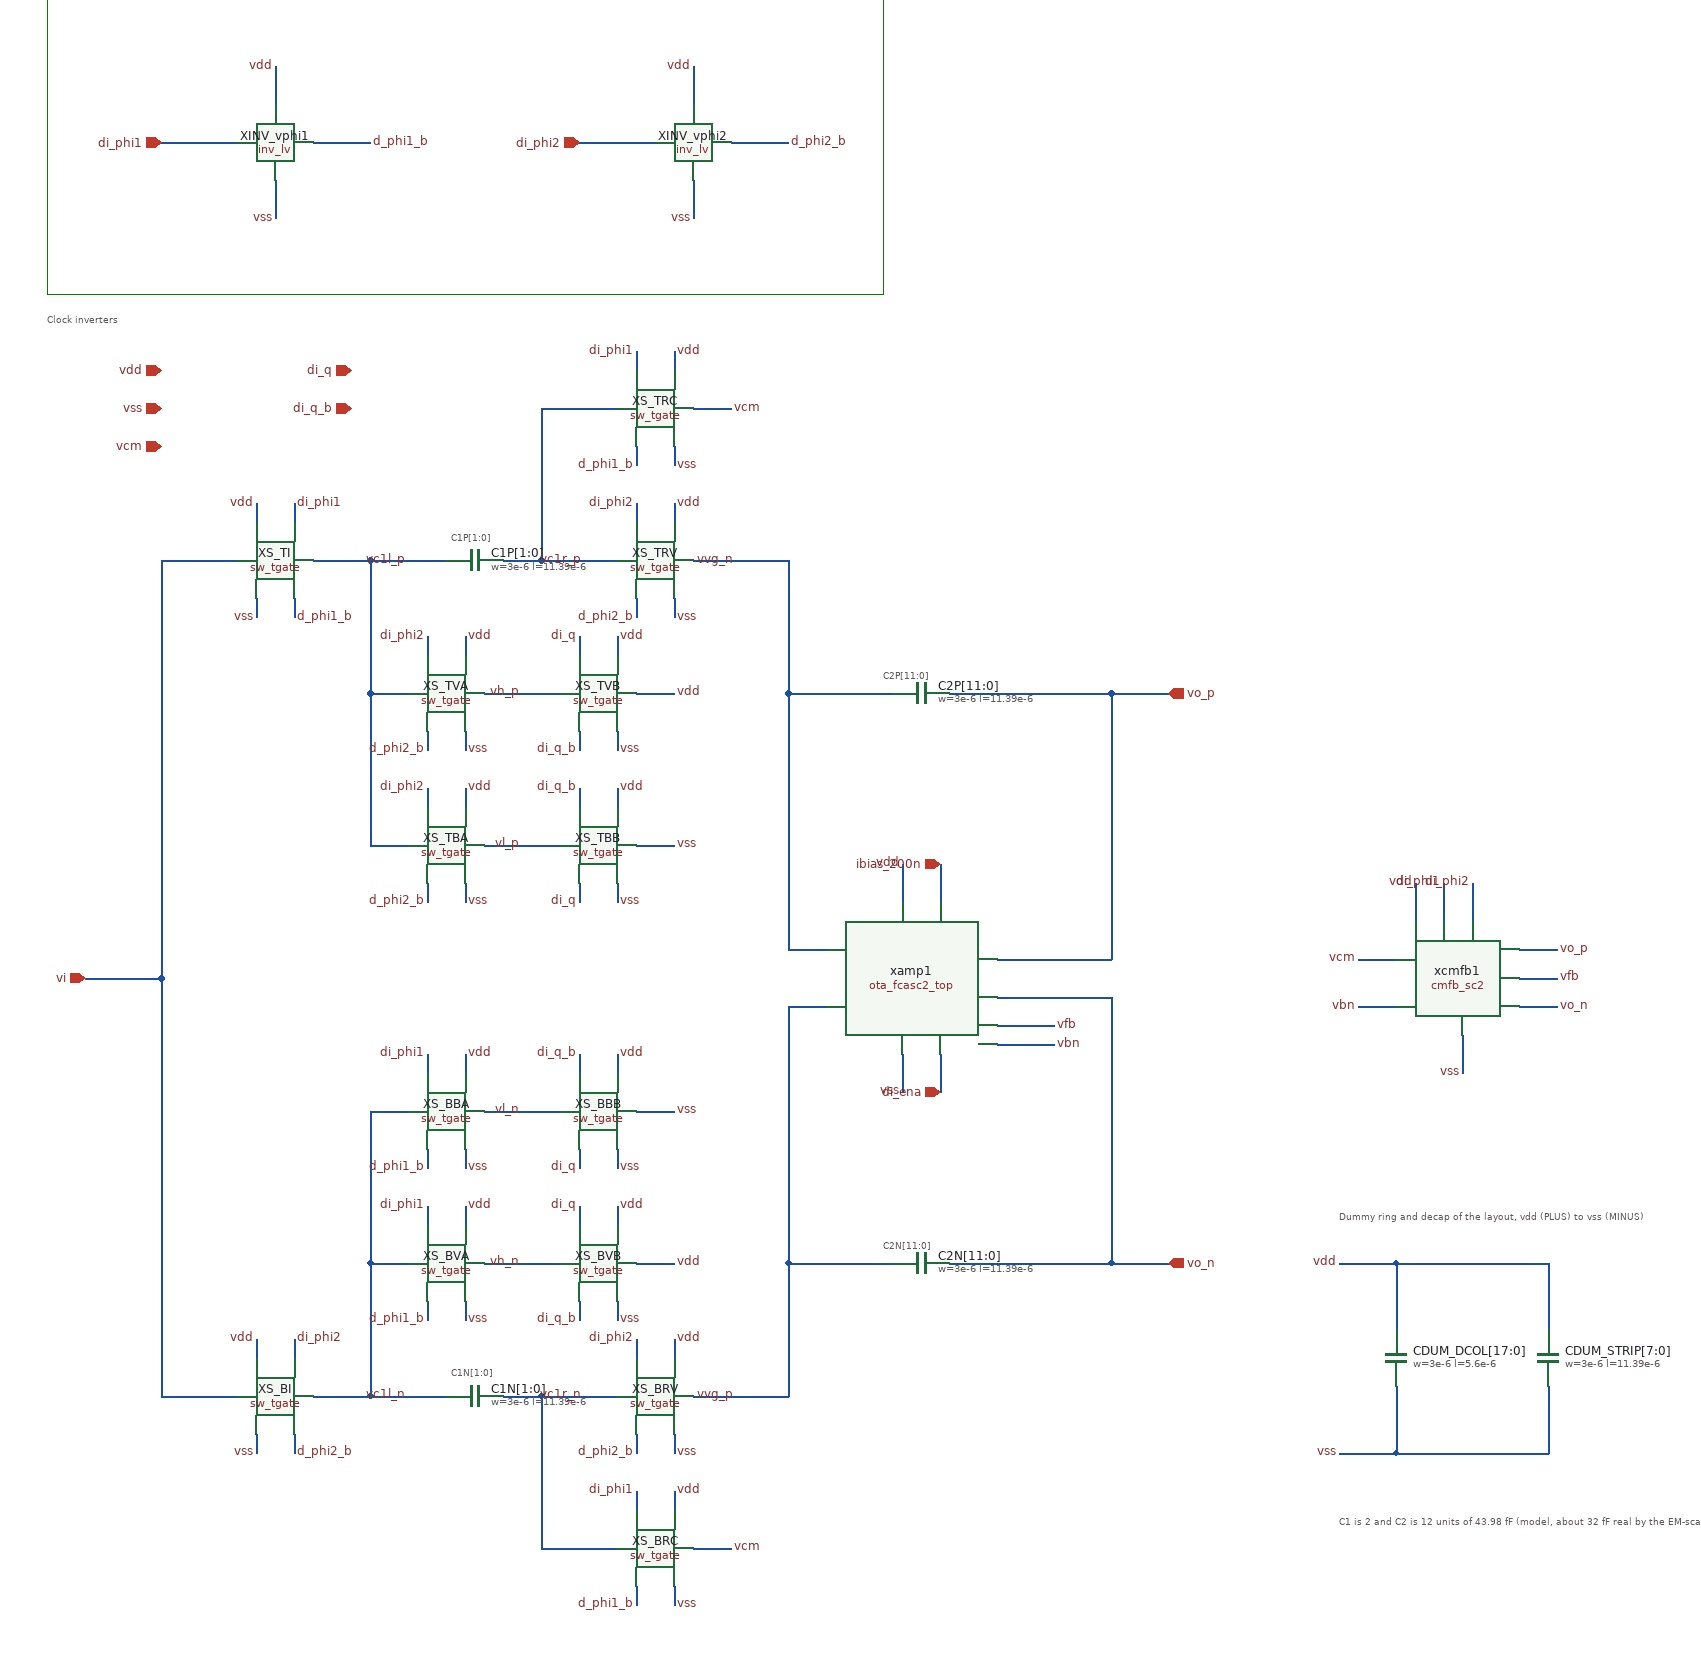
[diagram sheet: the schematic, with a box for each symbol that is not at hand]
v {xschem version=3.4.8RC file_version=1.3}
G {}
K {}
V {}
S {}
F {}
E {}
P 4 5 20 -1040 900 -1040 900 -720 20 -720 20 -1040 {dash = 8}
T {C1P[1:0]} 445 -476 0 0 0.2 0.2 {}
T {C2P[11:0]} 900 -330 0 0 0.2 0.2 {}
T {C1N[1:0]} 445 404 0 0 0.2 0.2 {}
T {C2N[11:0]} 900 270 0 0 0.2 0.2 {}
T {Clock inverters} 20 -705 0 0 0.25 0.25 {}
T {C1 is 2 and C2 is 12 units of 43.98 fF (model, about 32 fF real by the EM-scaled estimate) per half, C1/C2 = 1/6 by unit count, a1 = 2 C1/C2 = 1/3} 1380 560 0 0 0.25 0.25 {}
T {Dummy ring and decap of the layout, vdd (PLUS) to vss (MINUS)} 1380 240 0 0 0.3 0.3 {}
N 280 -500 280 -480 {lab=di_phi1}
N 280 -400 280 -380 {lab=d_phi1_b}
N 240 -500 240 -480 {lab=vdd}
N 240 -400 240 -380 {lab=vss}
N 140 -440 220 -440 {lab=vi}
N 360 -440 440 -440 {lab=vc1l_p}
N 360 -300 360 -140 {lab=vc1l_p}
N 360 -300 400 -300 {lab=vc1l_p}
N 360 -140 400 -140 {lab=vc1l_p}
N 420 -360 420 -340 {lab=di_phi2}
N 420 -260 420 -240 {lab=d_phi2_b}
N 460 -360 460 -340 {lab=vdd}
N 460 -260 460 -240 {lab=vss}
N 580 -360 580 -340 {lab=di_q}
N 580 -260 580 -240 {lab=di_q_b}
N 620 -360 620 -340 {lab=vdd}
N 620 -260 620 -240 {lab=vss}
N 480 -300 560 -300 {lab=vh_p}
N 640 -300 680 -300 {lab=vdd}
N 420 -200 420 -180 {lab=di_phi2}
N 420 -100 420 -80 {lab=d_phi2_b}
N 460 -200 460 -180 {lab=vdd}
N 460 -100 460 -80 {lab=vss}
N 580 -200 580 -180 {lab=di_q_b}
N 580 -100 580 -80 {lab=di_q}
N 620 -200 620 -180 {lab=vdd}
N 620 -100 620 -80 {lab=vss}
N 480 -140 560 -140 {lab=vl_p}
N 640 -140 680 -140 {lab=vss}
N 540 -440 620 -440 {lab=vc1r_p}
N 540 -600 540 -440 {lab=vc1r_p}
N 540 -600 620 -600 {lab=vc1r_p}
N 640 -660 640 -640 {lab=di_phi1}
N 640 -560 640 -540 {lab=d_phi1_b}
N 680 -660 680 -640 {lab=vdd}
N 680 -560 680 -540 {lab=vss}
N 640 -500 640 -480 {lab=di_phi2}
N 640 -400 640 -380 {lab=d_phi2_b}
N 680 -500 680 -480 {lab=vdd}
N 680 -400 680 -380 {lab=vss}
N 700 -600 740 -600 {lab=vcm}
N 700 -440 800 -440 {lab=vvg_n}
N 800 -300 800 -30 {lab=vvg_n}
N 800 -30 840 -30 {lab=vvg_n}
N 800 -300 910 -300 {lab=vvg_n}
N 970 -300 1140 -300 {lab=vo_p}
N 1140 -300 1200 -300 {lab=vo_p}
N 1140 -300 1140 -20 {lab=vo_p}
N 1020 -20 1140 -20 {lab=vo_p}
N 280 380 280 400 {lab=di_phi2}
N 280 480 280 500 {lab=d_phi2_b}
N 240 380 240 400 {lab=vdd}
N 240 480 240 500 {lab=vss}
N 140 440 220 440 {lab=vi}
N 360 440 440 440 {lab=vc1l_n}
N 360 300 360 440 {lab=vc1l_n}
N 360 300 400 300 {lab=vc1l_n}
N 360 140 400 140 {lab=vc1l_n}
N 420 240 420 260 {lab=di_phi1}
N 420 340 420 360 {lab=d_phi1_b}
N 460 240 460 260 {lab=vdd}
N 460 340 460 360 {lab=vss}
N 580 240 580 260 {lab=di_q}
N 580 340 580 360 {lab=di_q_b}
N 620 240 620 260 {lab=vdd}
N 620 340 620 360 {lab=vss}
N 480 300 560 300 {lab=vh_n}
N 640 300 680 300 {lab=vdd}
N 420 80 420 100 {lab=di_phi1}
N 420 180 420 200 {lab=d_phi1_b}
N 460 80 460 100 {lab=vdd}
N 460 180 460 200 {lab=vss}
N 580 80 580 100 {lab=di_q_b}
N 580 180 580 200 {lab=di_q}
N 620 80 620 100 {lab=vdd}
N 620 180 620 200 {lab=vss}
N 480 140 560 140 {lab=vl_n}
N 640 140 680 140 {lab=vss}
N 540 440 620 440 {lab=vc1r_n}
N 540 440 540 600 {lab=vc1r_n}
N 540 600 620 600 {lab=vc1r_n}
N 640 540 640 560 {lab=di_phi1}
N 640 640 640 660 {lab=d_phi1_b}
N 680 540 680 560 {lab=vdd}
N 680 640 680 660 {lab=vss}
N 640 380 640 400 {lab=di_phi2}
N 640 480 640 500 {lab=d_phi2_b}
N 680 380 680 400 {lab=vdd}
N 680 480 680 500 {lab=vss}
N 700 600 740 600 {lab=vcm}
N 700 440 800 440 {lab=vvg_p}
N 800 300 800 440 {lab=vvg_p}
N 800 30 840 30 {lab=vvg_p}
N 800 300 910 300 {lab=vvg_p}
N 970 300 1140 300 {lab=vo_n}
N 1140 300 1200 300 {lab=vo_n}
N 1140 20 1140 300 {lab=vo_n}
N 1020 20 1140 20 {lab=vo_n}
N 60 0 140 0 {lab=vi}
N 140 0 140 440 {lab=vi}
N 920 -120 920 -80 {lab=vdd}
N 960 -120 960 -80 {lab=ibias_200n}
N 920 80 920 120 {lab=vss}
N 960 80 960 120 {lab=di_ena}
N 1020 50 1080 50 {lab=vfb}
N 1020 70 1080 70 {lab=vbn}
N 1490 -100 1490 -60 {lab=di_phi1}
N 1520 -100 1520 -60 {lab=di_phi2}
N 1460 -100 1460 -60 {lab=vdd}
N 1510 60 1510 100 {lab=vss}
N 1400 -20 1440 -20 {lab=vcm}
N 1400 30 1440 30 {lab=vbn}
N 1570 -30 1610 -30 {lab=vo_p}
N 1570 0 1610 0 {lab=vfb}
N 1570 30 1610 30 {lab=vo_n}
N 140 -880 220 -880 {lab=di_phi1}
N 300 -880 360 -880 {lab=d_phi1_b}
N 260 -960 260 -920 {lab=vdd}
N 260 -840 260 -800 {lab=vss}
N 580 -880 660 -880 {lab=di_phi2}
N 740 -880 800 -880 {lab=d_phi2_b}
N 700 -960 700 -920 {lab=vdd}
N 700 -840 700 -800 {lab=vss}
N 1440 300 1440 370 {lab=vdd}
N 1440 430 1440 500 {lab=vss}
N 1600 300 1600 370 {lab=vdd}
N 1600 430 1600 500 {lab=vss}
N 300 -440 360 -440 {lab=vc1l_p}
N 360 -440 360 -300 {lab=vc1l_p}
N 500 -440 540 -440 {lab=vc1r_p}
N 800 -440 800 -300 {lab=vvg_n}
N 300 440 360 440 {lab=vc1l_n}
N 360 140 360 300 {lab=vc1l_n}
N 500 440 540 440 {lab=vc1r_n}
N 800 30 800 300 {lab=vvg_p}
N 140 -440 140 0 {lab=vi}
N 1380 300 1440 300 {lab=vdd}
N 1380 500 1440 500 {lab=vss}
N 1440 300 1600 300 {lab=vdd}
N 1440 500 1600 500 {lab=vss}
C {sw_tgate.sym} 260 -440 0 1 {name=XS_TI
}
C {sw_tgate.sym} 440 -300 0 0 {name=XS_TVA
}
C {sw_tgate.sym} 600 -300 0 0 {name=XS_TVB
}
C {sw_tgate.sym} 440 -140 0 0 {name=XS_TBA
}
C {sw_tgate.sym} 600 -140 0 0 {name=XS_TBB
}
C {cap_cmomf.sym} 470 -440 1 0 {name=C1P[1:0]
model=cap_cmomf
w=3e-6
l=11.39e-6
mmin=1
mmax=4
subblock=0
m=1
mm_ok=1
spiceprefix=X
hide_texts=true
}
C {sw_tgate.sym} 660 -440 0 0 {name=XS_TRV
}
C {sw_tgate.sym} 660 -600 0 0 {name=XS_TRC
}
C {sw_tgate.sym} 260 440 0 1 {name=XS_BI
}
C {sw_tgate.sym} 440 300 0 0 {name=XS_BVA
}
C {sw_tgate.sym} 600 300 0 0 {name=XS_BVB
}
C {sw_tgate.sym} 440 140 0 0 {name=XS_BBA
}
C {sw_tgate.sym} 600 140 0 0 {name=XS_BBB
}
C {cap_cmomf.sym} 470 440 1 0 {name=C1N[1:0]
model=cap_cmomf
w=3e-6
l=11.39e-6
mmin=1
mmax=4
subblock=0
m=1
mm_ok=1
spiceprefix=X
hide_texts=true
}
C {sw_tgate.sym} 660 440 0 0 {name=XS_BRV
}
C {sw_tgate.sym} 660 600 0 0 {name=XS_BRC
}
C {ipin.sym} 60 0 0 0 {name=p3 lab=vi}
C {ota_fcasc2_top.sym} 840 -30 0 0 {name=xamp1
}
C {ipin.sym} 960 -120 1 0 {name=p9 lab=ibias_200n}
C {ipin.sym} 960 120 3 0 {name=p10 lab=di_ena}
C {cap_cmomf.sym} 940 -300 3 0 {name=C2P[11:0]
model=cap_cmomf
w=3e-6
l=11.39e-6
mmin=1
mmax=4
subblock=0
m=1
mm_ok=1
spiceprefix=X
hide_texts=true
}
C {cap_cmomf.sym} 940 300 3 0 {name=C2N[11:0]
model=cap_cmomf
w=3e-6
l=11.39e-6
mmin=1
mmax=4
subblock=0
m=1
mm_ok=1
spiceprefix=X
hide_texts=true
}
C {cmfb_sc2.sym} 1440 -60 0 0 {name=xcmfb1
}
C {inv_lv.sym} 260 -880 0 0 {name=XINV_vphi1
}
C {ipin.sym} 140 -880 0 0 {name=p5 lab=di_phi1}
C {inv_lv.sym} 700 -880 0 0 {name=XINV_vphi2
}
C {ipin.sym} 580 -880 0 0 {name=p6 lab=di_phi2}
C {iopin.sym} 140 -640 2 0 {name=p1 lab=vdd}
C {iopin.sym} 140 -600 2 0 {name=p2 lab=vss}
C {ipin.sym} 140 -560 0 0 {name=p4 lab=vcm}
C {ipin.sym} 340 -640 0 0 {name=p7 lab=di_q}
C {ipin.sym} 340 -600 0 0 {name=p8 lab=di_q_b}
C {opin.sym} 1200 -300 0 0 {name=p11 lab=vo_p}
C {opin.sym} 1200 300 0 0 {name=p12 lab=vo_n}
C {cap_cmomf.sym} 1440 400 0 0 {name=CDUM_DCOL[17:0]
model=cap_cmomf
w=3e-6
l=5.6e-6
mmin=1
mmax=4
subblock=0
m=1
mm_ok=1
spiceprefix=X
}
C {cap_cmomf.sym} 1600 400 0 0 {name=CDUM_STRIP[7:0]
model=cap_cmomf
w=3e-6
l=11.39e-6
mmin=1
mmax=4
subblock=0
m=1
mm_ok=1
spiceprefix=X
}
C {lab_pin.sym} 280 -500 0 1 {name=l1 lab=di_phi1}
C {lab_pin.sym} 280 -380 0 1 {name=l2 lab=d_phi1_b}
C {lab_pin.sym} 240 -500 0 0 {name=l3 lab=vdd}
C {lab_pin.sym} 240 -380 0 0 {name=l4 lab=vss}
C {lab_wire.sym} 400 -440 0 0 {name=l5 lab=vc1l_p}
C {lab_pin.sym} 420 -360 0 0 {name=l6 lab=di_phi2}
C {lab_pin.sym} 420 -240 0 0 {name=l7 lab=d_phi2_b}
C {lab_pin.sym} 460 -360 0 1 {name=l8 lab=vdd}
C {lab_pin.sym} 460 -240 0 1 {name=l9 lab=vss}
C {lab_pin.sym} 580 -360 0 0 {name=l10 lab=di_q}
C {lab_pin.sym} 580 -240 0 0 {name=l11 lab=di_q_b}
C {lab_pin.sym} 620 -360 0 1 {name=l12 lab=vdd}
C {lab_pin.sym} 620 -240 0 1 {name=l13 lab=vss}
C {lab_wire.sym} 520 -300 0 0 {name=l14 lab=vh_p}
C {lab_pin.sym} 680 -300 0 1 {name=l15 lab=vdd}
C {lab_pin.sym} 420 -200 0 0 {name=l16 lab=di_phi2}
C {lab_pin.sym} 420 -80 0 0 {name=l17 lab=d_phi2_b}
C {lab_pin.sym} 460 -200 0 1 {name=l18 lab=vdd}
C {lab_pin.sym} 460 -80 0 1 {name=l19 lab=vss}
C {lab_pin.sym} 580 -200 0 0 {name=l20 lab=di_q_b}
C {lab_pin.sym} 580 -80 0 0 {name=l21 lab=di_q}
C {lab_pin.sym} 620 -200 0 1 {name=l22 lab=vdd}
C {lab_pin.sym} 620 -80 0 1 {name=l23 lab=vss}
C {lab_wire.sym} 520 -140 0 0 {name=l24 lab=vl_p}
C {lab_pin.sym} 680 -140 0 1 {name=l25 lab=vss}
C {lab_wire.sym} 585 -440 0 0 {name=l26 lab=vc1r_p}
C {lab_pin.sym} 640 -660 0 0 {name=l27 lab=di_phi1}
C {lab_pin.sym} 640 -540 0 0 {name=l28 lab=d_phi1_b}
C {lab_pin.sym} 680 -660 0 1 {name=l29 lab=vdd}
C {lab_pin.sym} 680 -540 0 1 {name=l30 lab=vss}
C {lab_pin.sym} 640 -500 0 0 {name=l31 lab=di_phi2}
C {lab_pin.sym} 640 -380 0 0 {name=l32 lab=d_phi2_b}
C {lab_pin.sym} 680 -500 0 1 {name=l33 lab=vdd}
C {lab_pin.sym} 680 -380 0 1 {name=l34 lab=vss}
C {lab_pin.sym} 740 -600 0 1 {name=l35 lab=vcm}
C {lab_wire.sym} 745 -440 0 0 {name=l36 lab=vvg_n}
C {lab_pin.sym} 280 380 0 1 {name=l37 lab=di_phi2}
C {lab_pin.sym} 280 500 0 1 {name=l38 lab=d_phi2_b}
C {lab_pin.sym} 240 380 0 0 {name=l39 lab=vdd}
C {lab_pin.sym} 240 500 0 0 {name=l40 lab=vss}
C {lab_wire.sym} 400 440 0 0 {name=l41 lab=vc1l_n}
C {lab_pin.sym} 420 240 0 0 {name=l42 lab=di_phi1}
C {lab_pin.sym} 420 360 0 0 {name=l43 lab=d_phi1_b}
C {lab_pin.sym} 460 240 0 1 {name=l44 lab=vdd}
C {lab_pin.sym} 460 360 0 1 {name=l45 lab=vss}
C {lab_pin.sym} 580 240 0 0 {name=l46 lab=di_q}
C {lab_pin.sym} 580 360 0 0 {name=l47 lab=di_q_b}
C {lab_pin.sym} 620 240 0 1 {name=l48 lab=vdd}
C {lab_pin.sym} 620 360 0 1 {name=l49 lab=vss}
C {lab_wire.sym} 520 300 0 0 {name=l50 lab=vh_n}
C {lab_pin.sym} 680 300 0 1 {name=l51 lab=vdd}
C {lab_pin.sym} 420 80 0 0 {name=l52 lab=di_phi1}
C {lab_pin.sym} 420 200 0 0 {name=l53 lab=d_phi1_b}
C {lab_pin.sym} 460 80 0 1 {name=l54 lab=vdd}
C {lab_pin.sym} 460 200 0 1 {name=l55 lab=vss}
C {lab_pin.sym} 580 80 0 0 {name=l56 lab=di_q_b}
C {lab_pin.sym} 580 200 0 0 {name=l57 lab=di_q}
C {lab_pin.sym} 620 80 0 1 {name=l58 lab=vdd}
C {lab_pin.sym} 620 200 0 1 {name=l59 lab=vss}
C {lab_wire.sym} 520 140 0 0 {name=l60 lab=vl_n}
C {lab_pin.sym} 680 140 0 1 {name=l61 lab=vss}
C {lab_wire.sym} 585 440 0 0 {name=l62 lab=vc1r_n}
C {lab_pin.sym} 640 540 0 0 {name=l63 lab=di_phi1}
C {lab_pin.sym} 640 660 0 0 {name=l64 lab=d_phi1_b}
C {lab_pin.sym} 680 540 0 1 {name=l65 lab=vdd}
C {lab_pin.sym} 680 660 0 1 {name=l66 lab=vss}
C {lab_pin.sym} 640 380 0 0 {name=l67 lab=di_phi2}
C {lab_pin.sym} 640 500 0 0 {name=l68 lab=d_phi2_b}
C {lab_pin.sym} 680 380 0 1 {name=l69 lab=vdd}
C {lab_pin.sym} 680 500 0 1 {name=l70 lab=vss}
C {lab_pin.sym} 740 600 0 1 {name=l71 lab=vcm}
C {lab_wire.sym} 745 440 0 0 {name=l72 lab=vvg_p}
C {lab_pin.sym} 920 -120 1 0 {name=l73 lab=vdd}
C {lab_pin.sym} 920 120 3 0 {name=l74 lab=vss}
C {lab_pin.sym} 1080 50 0 1 {name=l75 lab=vfb}
C {lab_pin.sym} 1080 70 0 1 {name=l76 lab=vbn}
C {lab_pin.sym} 1490 -100 1 0 {name=l77 lab=di_phi1}
C {lab_pin.sym} 1520 -100 1 0 {name=l78 lab=di_phi2}
C {lab_pin.sym} 1460 -100 1 0 {name=l79 lab=vdd}
C {lab_pin.sym} 1510 100 3 0 {name=l80 lab=vss}
C {lab_pin.sym} 1400 -20 0 0 {name=l81 lab=vcm}
C {lab_pin.sym} 1400 30 0 0 {name=l82 lab=vbn}
C {lab_pin.sym} 1610 -30 0 1 {name=l83 lab=vo_p}
C {lab_pin.sym} 1610 0 0 1 {name=l84 lab=vfb}
C {lab_pin.sym} 1610 30 0 1 {name=l85 lab=vo_n}
C {lab_pin.sym} 360 -880 0 1 {name=l86 lab=d_phi1_b}
C {lab_pin.sym} 260 -960 1 0 {name=l87 lab=vdd}
C {lab_pin.sym} 260 -800 3 0 {name=l88 lab=vss}
C {lab_pin.sym} 800 -880 0 1 {name=l89 lab=d_phi2_b}
C {lab_pin.sym} 700 -960 1 0 {name=l90 lab=vdd}
C {lab_pin.sym} 700 -800 3 0 {name=l91 lab=vss}
C {lab_pin.sym} 1380 300 0 0 {name=l92 lab=vdd}
C {lab_pin.sym} 1380 500 0 0 {name=l93 lab=vss}
C {title.sym} 160 760 0 0 {name=l0 author="(c) 2026 Michael Koefinger"}
